VERSION 5.8 ;
BUSBITCHARS "[]" ;
DIVIDERCHAR "/" ;
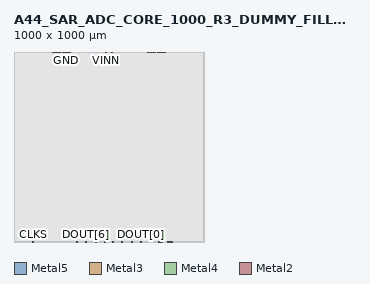
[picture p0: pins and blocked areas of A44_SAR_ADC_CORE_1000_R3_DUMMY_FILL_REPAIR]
MACRO A44_SAR_ADC_CORE_1000_R3_DUMMY_FILL_REPAIR
  CLASS BLOCK ;
  ORIGIN 0.000 0.000 ;
  FOREIGN A44_SAR_ADC_CORE_1000_R3_DUMMY_FILL_REPAIR 0.000 0.000 ;
  SIZE 1000.000 BY 1000.000 ;
  PIN VDD
    DIRECTION INOUT ;
    USE POWER ;
    PORT
      LAYER Metal5 ;
        RECT 758.000 0.000 782.000 4.000 ;
      LAYER Metal5 ;
        RECT 205.000 997.000 245.000 1000.000 ;
      LAYER Metal5 ;
        RECT 755.000 997.000 795.000 1000.000 ;
    END
  END VDD
  PIN GND
    DIRECTION INOUT ;
    USE GROUND ;
    PORT
      LAYER Metal5 ;
        RECT 808.000 0.000 832.000 4.000 ;
      LAYER Metal5 ;
        RECT 255.000 997.000 295.000 1000.000 ;
      LAYER Metal5 ;
        RECT 705.000 997.000 745.000 1000.000 ;
    END
  END GND
  PIN VREFP
    DIRECTION INPUT ;
    USE SIGNAL ;
    PORT
      LAYER Metal5 ;
        RECT 558.000 998.000 562.000 1000.000 ;
    END
  END VREFP
  PIN VREFN
    DIRECTION INPUT ;
    USE SIGNAL ;
    PORT
      LAYER Metal5 ;
        RECT 438.000 998.000 442.000 1000.000 ;
    END
  END VREFN
  PIN VINP
    DIRECTION INPUT ;
    USE SIGNAL ;
    PORT
      LAYER Metal3 ;
        RECT 513.000 998.000 517.000 1000.000 ;
    END
  END VINP
  PIN VINN
    DIRECTION INPUT ;
    USE SIGNAL ;
    PORT
      LAYER Metal3 ;
        RECT 483.000 998.000 487.000 1000.000 ;
    END
  END VINN
  PIN CLKS
    DIRECTION INPUT ;
    USE CLOCK ;
    PORT
      LAYER Metal4 ;
        RECT 98.000 0.000 102.000 2.000 ;
    END
  END CLKS
  PIN DOUT[7]
    DIRECTION OUTPUT ;
    USE SIGNAL ;
    PORT
      LAYER Metal2 ;
        RECT 328.000 0.000 332.000 2.000 ;
    END
  END DOUT[7]
  PIN DOUT[6]
    DIRECTION OUTPUT ;
    USE SIGNAL ;
    PORT
      LAYER Metal2 ;
        RECT 378.000 0.000 382.000 2.000 ;
    END
  END DOUT[6]
  PIN DOUT[5]
    DIRECTION OUTPUT ;
    USE SIGNAL ;
    PORT
      LAYER Metal2 ;
        RECT 428.000 0.000 432.000 2.000 ;
    END
  END DOUT[5]
  PIN DOUT[4]
    DIRECTION OUTPUT ;
    USE SIGNAL ;
    PORT
      LAYER Metal2 ;
        RECT 478.000 0.000 482.000 2.000 ;
    END
  END DOUT[4]
  PIN DOUT[3]
    DIRECTION OUTPUT ;
    USE SIGNAL ;
    PORT
      LAYER Metal2 ;
        RECT 518.000 0.000 522.000 2.000 ;
    END
  END DOUT[3]
  PIN DOUT[2]
    DIRECTION OUTPUT ;
    USE SIGNAL ;
    PORT
      LAYER Metal2 ;
        RECT 568.000 0.000 572.000 2.000 ;
    END
  END DOUT[2]
  PIN DOUT[1]
    DIRECTION OUTPUT ;
    USE SIGNAL ;
    PORT
      LAYER Metal2 ;
        RECT 618.000 0.000 622.000 2.000 ;
    END
  END DOUT[1]
  PIN DOUT[0]
    DIRECTION OUTPUT ;
    USE SIGNAL ;
    PORT
      LAYER Metal2 ;
        RECT 668.000 0.000 672.000 2.000 ;
    END
  END DOUT[0]
  OBS
    LAYER Metal1 ;
      RECT 0.000 0.000 1000.000 1000.000 ;
    LAYER Metal2 ;
      RECT 4.000 4.000 996.000 996.000 ;
    LAYER Metal3 ;
      RECT 4.000 4.000 996.000 996.000 ;
    LAYER Metal4 ;
      RECT 4.000 4.000 996.000 996.000 ;
    LAYER Metal5 ;
      RECT 4.000 4.000 996.000 996.000 ;
  END
END A44_SAR_ADC_CORE_1000_R3_DUMMY_FILL_REPAIR
END LIBRARY
